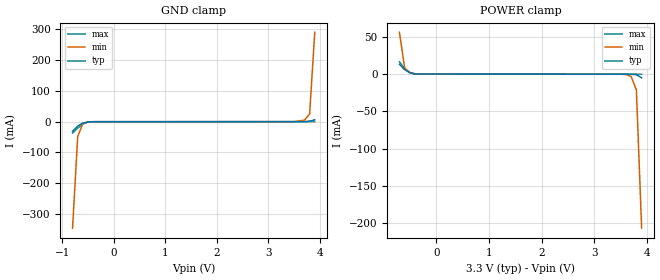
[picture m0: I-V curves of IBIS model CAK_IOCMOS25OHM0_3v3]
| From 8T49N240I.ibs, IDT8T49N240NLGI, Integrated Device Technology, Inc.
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| 3.25758e+00   -2.17526e-02   -5.28437e-01   -1.11612e-02
| 3.33333e+00   -5.02557e-02   -7.41905e-01   -2.20995e-02
| 3.40909e+00   -2.62296e-01   -9.55738e-01   -3.45860e-02
| 3.48485e+00   -5.48283e-01   -1.16984e+00   -4.61839e-02
| 3.56061e+00   -8.34620e-01   -1.38416e+00   -9.03549e-02
| 3.63636e+00   -1.12128e+00   -1.59867e+00   -4.17005e-01
| 3.71212e+00   -1.40822e+00   -1.81336e+00   -7.83863e-01
| 3.78788e+00   -1.69544e+00   -2.02823e+00   -1.15106e+00
| 3.86364e+00   -1.98290e+00   -2.24326e+00   -1.51854e+00
| 3.93939e+00   -2.27059e+00   -2.45845e+00   -1.88629e+00
| 4.01515e+00   -2.55849e+00   -2.67380e+00   -2.25425e+00
| 4.09091e+00   -2.84658e+00   -2.88929e+00   -2.62240e+00
| 4.16667e+00   -3.13483e+00   -3.10491e+00   -2.99072e+00
| 4.24242e+00   -3.42324e+00   -3.32067e+00   -3.35917e+00
| 4.31818e+00   -3.71177e+00   -3.53656e+00   -3.72774e+00
| 4.39394e+00   -4.00043e+00   -3.75256e+00   -4.09641e+00
| 4.46970e+00   -4.28920e+00   -3.96868e+00   -4.46517e+00
| 4.54545e+00   -4.57807e+00   -4.18490e+00   -4.83401e+00
| 4.62121e+00   -4.86701e+00   -4.40122e+00   -5.20293e+00
| 4.69697e+00   -5.15604e+00   -4.61763e+00   -5.57191e+00
| 4.77273e+00   -5.44513e+00   -4.83413e+00   -5.94093e+00
| 4.84848e+00   -5.73428e+00   -5.05072e+00   -6.31000e+00
| 4.92424e+00   -6.02348e+00   -5.26738e+00   -6.67909e+00
| 5.00000e+00   -6.31272e+00   -5.48412e+00   -7.04821e+00
[Model] CAK_IOCMOS25OHM0_3v3
Model_type   Input
Polarity   Non-Inverting
Vinl = 0.8V
Vinh = 2.0V
|   typ   min   max
C_comp   2pF   1.5pF   2.5pF
|   typ   min   max
[Voltage range]   3.3V   3.135V   3.465V
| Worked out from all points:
|   GND clamp passes 1 mA (typ) near -0.50 V on its own axis
|   POWER clamp passes 1 mA (typ) near -0.45 V on its own axis
[GND_clamp]
|Voltage   I (typ)   I (min)   I (max)
|Note, modeling breaks down at 250mA and above.  This is well beyond the functional   |
|operating range of the device.  Should this scenario occur, catastrophic failure and   |
|possible damage to the device and/or board is of higher concern than the I-V curve   |
|behavior.  The IBIS checker will flag currents in excess of 10A with warnings.  Lines   |
|with currents in excess of 0.35 A have been commented out.  The points still remain|
|available to the user if the user desires to use them.   |
|-3.30000e+00   -2.67880e+01   -2.11304e+01   -3.31620e+01
|-3.20000e+00   -2.56708e+01   -2.02932e+01   -3.17348e+01
|-3.10000e+00   -2.45536e+01   -1.94561e+01   -3.03075e+01
|-3.00000e+00   -2.34365e+01   -1.86191e+01   -2.88803e+01
|-2.90000e+00   -2.23193e+01   -1.77821e+01   -2.74530e+01
|-2.80000e+00   -2.12022e+01   -1.69453e+01   -2.60257e+01
|-2.70000e+00   -2.00852e+01   -1.61085e+01   -2.45984e+01
|-2.60000e+00   -1.89682e+01   -1.52719e+01   -2.31711e+01
|-2.50000e+00   -1.78512e+01   -1.44354e+01   -2.17438e+01
|-2.40000e+00   -1.67343e+01   -1.35990e+01   -2.03165e+01
|-2.30000e+00   -1.56175e+01   -1.27628e+01   -1.88893e+01
|-2.20000e+00   -1.45008e+01   -1.19267e+01   -1.74621e+01
|-2.10000e+00   -1.33842e+01   -1.10908e+01   -1.60349e+01
|-2.00000e+00   -1.22678e+01   -1.02551e+01   -1.46078e+01
|-1.90000e+00   -1.11515e+01   -9.41957e+00   -1.31808e+01
|-1.80000e+00   -1.00354e+01   -8.58426e+00   -1.17540e+01
|-1.70000e+00   -8.91950e+00   -7.74918e+00   -1.03273e+01
|-1.60000e+00   -7.80386e+00   -6.91434e+00   -8.90076e+00
|-1.50000e+00   -6.68850e+00   -6.07976e+00   -7.47445e+00
|-1.40000e+00   -5.57349e+00   -5.24546e+00   -6.04840e+00
|-1.30000e+00   -4.45885e+00   -4.41145e+00   -4.62267e+00
|-1.20000e+00   -3.34464e+00   -3.57774e+00   -3.19734e+00
|-1.10000e+00   -2.23090e+00   -2.74437e+00   -1.77249e+00
|-1.00000e+00   -1.11769e+00   -1.91140e+00   -4.23919e-01
|-9.00000e-01   -2.42978e-01   -1.07895e+00   -5.71820e-02
-800mV    -31.58mA   -346.5mA   -37.13mA
-700mV    -14.02mA   -47.95mA   -20.86mA
-600mV    -4.891mA   -5.99mA    -7.57mA
-500mV    -845.1uA   -939.6uA   -1.201mA
-400mV    -124.1uA   -152.8uA   -141.9uA
3.5V      4.074uA    131uA      805.5nA
3.7V      188uA      4.818mA    5.575uA
3.8V      1.749mA    25.01mA    23.47uA
3.9V      6.005mA    290.6mA    518.2uA
| 4.00000e+00   1.31613e-02   1.29161e+00   3.67695e-03
| 4.10000e+00   2.82381e-02   2.43119e+00   1.03297e-02
| 4.20000e+00   3.33592e-01   3.57106e+00   2.01811e-02
| 4.30000e+00   1.73507e+00   4.71130e+00   2.97871e-02
| 4.40000e+00   3.25730e+00   5.85191e+00   7.66204e-02
| 4.50000e+00   4.78003e+00   6.99289e+00   1.34066e+00
| 4.60000e+00   6.30325e+00   8.13425e+00   3.28748e+00
| 4.70000e+00   7.82696e+00   9.27597e+00   5.23493e+00
| 4.80000e+00   9.35115e+00   1.04181e+01   7.18299e+00
| 4.90000e+00   1.08758e+01   1.15605e+01   9.13163e+00
| 5.00000e+00   1.24009e+01   1.27033e+01   1.10808e+01
| 5.10000e+00   1.39264e+01   1.38465e+01   1.30306e+01
| 5.20000e+00   1.54524e+01   1.49901e+01   1.49808e+01
| 5.30000e+00   1.69788e+01   1.61340e+01   1.69316e+01
| 5.40000e+00   1.85056e+01   1.72783e+01   1.88828e+01
| 5.50000e+00   2.00329e+01   1.84230e+01   2.08345e+01
| 5.60000e+00   2.15605e+01   1.95681e+01   2.27867e+01
| 5.70000e+00   2.30886e+01   2.07137e+01   2.47393e+01
| 5.80000e+00   2.46171e+01   2.18596e+01   2.66923e+01
| 5.90000e+00   2.61460e+01   2.30059e+01   2.86458e+01
| 6.00000e+00   2.76753e+01   2.41528e+01   3.05996e+01
| 6.10000e+00   2.92051e+01   2.53000e+01   3.25539e+01
| 6.20000e+00   3.07353e+01   2.64478e+01   3.45086e+01
| 6.30000e+00   3.22660e+01   2.75961e+01   3.64638e+01
| 6.40000e+00   3.37972e+01   2.87449e+01   3.84193e+01
| 6.50000e+00   3.53288e+01   2.98943e+01   4.03753e+01
| 6.60000e+00   3.68610e+01   3.10443e+01   4.23318e+01
[Power_clamp]
|Voltage   I (typ)   I (min)   I (max)
|Note, modeling breaks down at 250mA and above.  This is well beyond the functional   |
|operating range of the device.  Should this scenario occur, catastrophic failure and   |
|possible damage to the device and/or board is of higher concern than the I-V curve   |
|behavior.  The IBIS checker will flag currents in excess of 10A with warnings.  Lines   |
|with currents in excess of 0.35 A have been commented out.  The points still remain|
|available to the user if the user desires to use them.   |
|-3.30000e+00   3.68610e+01   2.91586e+01   4.55611e+01
|-3.20000e+00   3.53288e+01   2.80096e+01   4.36038e+01
|-3.10000e+00   3.37972e+01   2.68611e+01   4.16470e+01
|-3.00000e+00   3.22660e+01   2.57132e+01   3.96907e+01
|-2.90000e+00   3.07353e+01   2.45657e+01   3.77348e+01
|-2.80000e+00   2.92051e+01   2.34187e+01   3.57794e+01
|-2.70000e+00   2.76753e+01   2.22722e+01   3.38244e+01
|-2.60000e+00   2.61460e+01   2.11261e+01   3.18699e+01
|-2.50000e+00   2.46171e+01   1.99805e+01   2.99157e+01
|-2.40000e+00   2.30886e+01   1.88352e+01   2.79620e+01
|-2.30000e+00   2.15605e+01   1.76904e+01   2.60087e+01
|-2.20000e+00   2.00329e+01   1.65459e+01   2.40558e+01
|-2.10000e+00   1.85056e+01   1.54019e+01   2.21034e+01
|-2.00000e+00   1.69788e+01   1.42582e+01   2.01514e+01
|-1.90000e+00   1.54524e+01   1.31148e+01   1.81999e+01
|-1.80000e+00   1.39264e+01   1.19719e+01   1.62488e+01
|-1.70000e+00   1.24009e+01   1.08293e+01   1.42982e+01
|-1.60000e+00   1.08758e+01   9.68708e+00   1.23481e+01
|-1.50000e+00   9.35115e+00   8.54522e+00   1.03986e+01
|-1.40000e+00   7.82696e+00   7.40374e+00   8.44954e+00
|-1.30000e+00   6.30325e+00   6.26262e+00   6.50110e+00
|-1.20000e+00   4.78003e+00   5.12188e+00   4.55325e+00
|-1.10000e+00   3.25730e+00   3.98151e+00   2.60602e+00
|-1.00000e+00   1.73507e+00   2.84150e+00   6.65694e-01
|-9.00000e-01   3.33592e-01   1.70183e+00   4.16232e-02
|-8.00000e-01   2.82381e-02   5.79165e-01   2.67180e-02
-700mV    13.16mA    56.15mA    16.45mA
-600mV    6.005mA    8.033mA    7.61mA
-500mV    1.749mA    1.985mA    2.168mA
-400mV    188uA      310.8uA    178.2uA
3.5V      -69.76uA   -98.2uA    -80.55uA
3.6V      -73.38uA   -468.2uA   -82.85uA
3.7V      -124.1uA   -3.105mA   -85.19uA
3.8V      -845.1uA   -21.26mA   -91.47uA
3.9V      -4.891mA   -207mA     -262.6uA
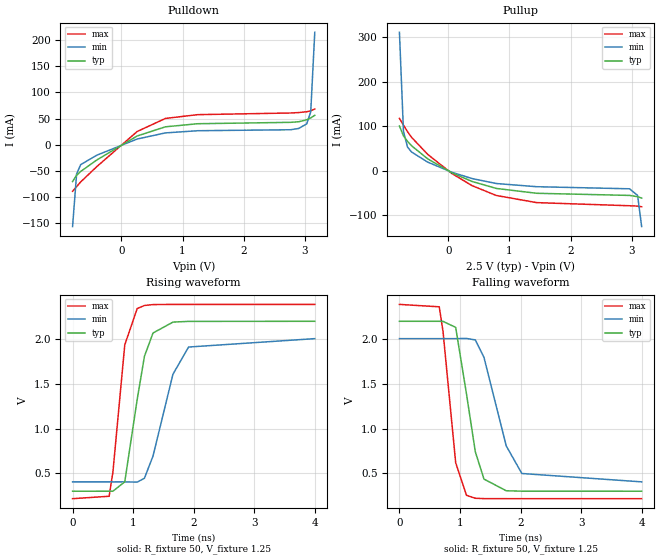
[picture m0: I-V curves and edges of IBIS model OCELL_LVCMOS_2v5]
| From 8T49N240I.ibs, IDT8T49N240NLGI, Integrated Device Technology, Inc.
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[Model] OCELL_LVCMOS_2v5
Model_type   Output
Polarity   Non-Inverting
|   typ   min   max
C_comp   2pF   1.5pF   2.5pF
Vmeas = 1.25V
Rref = 50
Cref = 0
Vref = 1.25V
|   typ   min   max
[Voltage range]   2.5V   2.375V   2.625V
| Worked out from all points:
|   slope of the pulldown table from 0 to 0.375 V, typ, clamps not added: 16.6 ohm
|   slope of the pullup table from 0 to 0.375 V, typ, clamps not added: 16.3 ohm
|   rising waveform, R_fixture 50, V_fixture 1.25: 20-80 % time 250ps typ, 356ps min, 180ps max; typ from 0.3 V to 2.2 V
|   falling waveform, R_fixture 50, V_fixture 1.25: 20-80 % time 254ps typ, 365ps min, 183ps max; typ from 2.2 V to 0.3 V
[Pulldown]
|Voltage   I (typ)   I (min)   I (max)
|Note, modeling breaks down at 250mA and above.  This is well beyond the functional   |
|operating range of the device.  Should this scenario occur, catastrophic failure and   |
|possible damage to the device and/or board is of higher concern than the I-V curve   |
|behavior.  The IBIS checker will flag currents in excess of 10A with warnings.  Lines   |
|with currents in excess of 0.35 A have been commented out.  The points still remain|
|available to the user if the user desires to use them.   |
|-2.20000e+00   -1.47234e+01   -1.29922e+01   -1.76718e+01
|-1.90000e+00   -1.13870e+01   -1.02147e+01   -1.34078e+01
|-1.60000e+00   -8.05069e+00   -7.43744e+00   -9.14425e+00
|-1.30000e+00   -4.71452e+00   -4.66038e+00   -4.88193e+00
|-1.00000e+00   -1.37872e+00   -1.88338e+00   -6.18804e-01
|-9.99000e-01   -1.36761e+00   -1.87412e+00   -6.04590e-01
|-9.32920e-01   -6.32942e-01   -1.26251e+00   -1.30309e-01
|-8.66839e-01   -1.33973e-01   -6.50974e-01   -9.78635e-02
-800.8mV  -70.24mA   -156.4mA   -88.93mA
-734.7mV  -58.48mA   -55.98mA   -80.19mA
-668.6mV  -51.18mA   -38.1mA    -71.19mA
-404.3mV  -29.17mA   -20.02mA   -41.85mA
256.5mV   16.72mA    10.9mA     25.23mA
719.1mV   34.24mA    22.61mA    50.25mA
1.248V    40.16mA    26.79mA    57.49mA
2.768V    42.8mA     28.65mA    60.67mA
2.9V      43.9mA     31.11mA    61.49mA
3.032V    47.65mA    39.85mA    63.04mA
3.098V    51.28mA    62.74mA    64.91mA
3.164V    56.14mA    214.9mA    68.27mA
| 3.23015e+00   6.27700e-02   1.07011e+00   7.31405e-02
| 3.29623e+00   7.75504e-02   2.32136e+00   7.94722e-02
| 3.36231e+00   1.89154e-01   3.57597e+00   8.71327e-02
| 3.42839e+00   1.12551e+00   4.83077e+00   9.48018e-02
| 3.49447e+00   2.63066e+00   6.08576e+00   1.03558e-01
| 3.56055e+00   4.13822e+00   7.34094e+00   1.69861e-01
| 3.62663e+00   5.64602e+00   8.59632e+00   1.20869e+00
| 3.69271e+00   7.15406e+00   9.85190e+00   3.13574e+00
| 3.75879e+00   8.66234e+00   1.11077e+01   5.06397e+00
| 3.82487e+00   1.01709e+01   1.23636e+01   6.99250e+00
| 3.89095e+00   1.16796e+01   1.36198e+01   8.92133e+00
| 3.95703e+00   1.31886e+01   1.48761e+01   1.08505e+01
| 4.02311e+00   1.46979e+01   1.61327e+01   1.27799e+01
| 4.08920e+00   1.62074e+01   1.73894e+01   1.47096e+01
| 4.15528e+00   1.77171e+01   1.86464e+01   1.66397e+01
| 4.22136e+00   1.92271e+01   1.99035e+01   1.85700e+01
| 4.28744e+00   2.07373e+01   2.11609e+01   2.05005e+01
| 4.35352e+00   2.22478e+01   2.24185e+01   2.24314e+01
| 4.41960e+00   2.37585e+01   2.36762e+01   2.43626e+01
| 4.48568e+00   2.52695e+01   2.49342e+01   2.62941e+01
| 4.55176e+00   2.67807e+01   2.61924e+01   2.82260e+01
| 4.61784e+00   2.82921e+01   2.74508e+01   3.01581e+01
| 4.68392e+00   2.98039e+01   2.87095e+01   3.20906e+01
| 4.75000e+00   3.13158e+01   2.99683e+01   3.40234e+01
| 4.75100e+00   3.13387e+01   2.99874e+01   3.40527e+01
| 4.80080e+00   3.24784e+01   3.09363e+01   3.55095e+01
| 4.85060e+00   3.36182e+01   3.18853e+01   3.69666e+01
| 4.90040e+00   3.47581e+01   3.28344e+01   3.84238e+01
| 4.95020e+00   3.58983e+01   3.37837e+01   3.98812e+01
| 5.00000e+00   3.70385e+01   3.47331e+01   4.13388e+01
[Pullup]
|Voltage   I (typ)   I (min)   I (max)
|Note, modeling breaks down at 250mA and above.  This is well beyond the functional   |
|operating range of the device.  Should this scenario occur, catastrophic failure and   |
|possible damage to the device and/or board is of higher concern than the I-V curve   |
|behavior.  The IBIS checker will flag currents in excess of 10A with warnings.  Lines   |
|with currents in excess of 0.35 A have been commented out.  The points still remain|
|available to the user if the user desires to use them.   |
|-2.20000e+00   3.02541e+01   2.67088e+01   3.63095e+01
|-1.90000e+00   2.33839e+01   2.09894e+01   2.75277e+01
|-1.60000e+00   1.65168e+01   1.52730e+01   1.87492e+01
|-1.30000e+00   9.65279e+00   9.55943e+00   9.97348e+00
|-1.00000e+00   2.79120e+00   3.84826e+00   1.20217e+00
|-9.99000e-01   2.76833e+00   3.82923e+00   1.17395e+00
|-9.32920e-01   1.25722e+00   2.57145e+00   1.97091e-01
|-8.66839e-01   2.37533e-01   1.31358e+00   1.32771e-01
-800.8mV  101.1mA    311.5mA    118.1mA
-734.7mV  78.81mA    89.07mA    102.8mA
-668.6mV  66.56mA    53.57mA    88.29mA
-602.5mV  56.6mA     42.56mA    75.59mA
-338.2mV  27.17mA    19.82mA    37.17mA
58.29mV   -4.132mA   -2.995mA   -5.792mA
388.7mV   -23.68mA   -17.13mA   -33.14mA
785.2mV   -39.34mA   -28.29mA   -55.16mA
1.446V    -50.22mA   -35.44mA   -71.2mA
2.966V    -55mA      -40.13mA   -78.22mA
3.098V    -57.9mA    -55.08mA   -78.97mA
3.164V    -61.03mA   -125mA     -80.49mA
| 3.23015e+00   -6.54678e-02   -5.43615e-01   -8.36409e-02
| 3.29623e+00   -7.42145e-02   -1.15365e+00   -8.83529e-02
| 3.36231e+00   -1.27209e-01   -1.76391e+00   -9.42530e-02
| 3.42839e+00   -5.84197e-01   -2.37432e+00   -1.00556e-01
| 3.49447e+00   -1.31730e+00   -2.98487e+00   -1.07568e-01
| 3.56055e+00   -2.05063e+00   -3.59552e+00   -1.41420e-01
| 3.62663e+00   -2.78416e+00   -4.20628e+00   -6.47768e-01
| 3.69271e+00   -3.51789e+00   -4.81712e+00   -1.58557e+00
| 3.75879e+00   -4.25179e+00   -5.42804e+00   -2.52351e+00
| 3.82487e+00   -4.98583e+00   -6.03904e+00   -3.46154e+00
| 3.89095e+00   -5.71999e+00   -6.65012e+00   -4.39967e+00
| 3.95703e+00   -6.45426e+00   -7.26126e+00   -5.33788e+00
| 4.02311e+00   -7.18862e+00   -7.87248e+00   -6.27622e+00
| 4.08920e+00   -7.92307e+00   -8.48376e+00   -7.21475e+00
| 4.15528e+00   -8.65759e+00   -9.09510e+00   -8.15347e+00
| 4.22136e+00   -9.39219e+00   -9.70650e+00   -9.09237e+00
| 4.28744e+00   -1.01269e+01   -1.03180e+01   -1.00314e+01
| 4.35352e+00   -1.08616e+01   -1.09295e+01   -1.09706e+01
| 4.41960e+00   -1.15964e+01   -1.15410e+01   -1.19098e+01
| 4.48568e+00   -1.23312e+01   -1.21527e+01   -1.28491e+01
| 4.55176e+00   -1.30661e+01   -1.27643e+01   -1.37885e+01
| 4.61784e+00   -1.38011e+01   -1.33761e+01   -1.47280e+01
| 4.68392e+00   -1.45361e+01   -1.39878e+01   -1.56675e+01
| 4.75000e+00   -1.52711e+01   -1.45997e+01   -1.66071e+01
| 4.75100e+00   -1.52823e+01   -1.46089e+01   -1.66213e+01
| 4.80080e+00   -1.58363e+01   -1.50701e+01   -1.73295e+01
| 4.85060e+00   -1.63903e+01   -1.55312e+01   -1.80376e+01
| 4.90040e+00   -1.69444e+01   -1.59924e+01   -1.87459e+01
| 4.95020e+00   -1.74985e+01   -1.64536e+01   -1.94541e+01
| 5.00000e+00   -1.80526e+01   -1.69149e+01   -2.01625e+01
[Ramp]
|   typ   min   max
dV/dt_r   1.141/0.25n   0.963/0.356n   1.305/0.18n
dV/dt_f   1.144/0.255n   0.964/0.366n   1.309/0.183n
R_load =   50.0000
[Rising Waveform]
R_fixture = 50
V_fixture = 1.25   |Vcc_typ
V_fixture_min = 1.1875 |Vcc_min
V_fixture_max = 1.3125 |Vcc_max
C_fixture = 0.0p
| Time   typ   min   max
0s        300mV      404.6mV    216.5mV
604.4ps   300.1mV    404.6mV    243.5mV
666.7ps   300.2mV    404.5mV    515.8mV
862.2ps   405.2mV    404.7mV    1.937V
1.067ns   1.325V     401.7mV    2.343V
1.187ns   1.809V     445.1mV    2.378V
1.329ns   2.07V      693.7mV    2.388V
1.658ns   2.192V     1.609V     2.39V
1.916ns   2.2V       1.913V     2.39V
4ns       2.201V     2.007V     2.39V
[Falling Waveform]
R_fixture = 50
V_fixture = 1.25   |Vcc_typ
V_fixture_min = 1.1875 |Vcc_min
V_fixture_max = 1.3125 |Vcc_max
C_fixture = 0.0p
| Time   typ   min   max
0s        2.201V     2.007V     2.39V
657.8ps   2.201V     2.007V     2.363V
720ps     2.2V       2.007V     2.086V
928.9ps   2.133V     2.007V     619.1mV
1.107ns   1.39V      2.009V     254.2mV
1.253ns   741.6mV    1.993V     221.1mV
1.396ns   435.8mV    1.798V     217.1mV
1.764ns   304.7mV    806.2mV    216.5mV
2.022ns   300.5mV    498.1mV    216.5mV
4ns       300mV      404.6mV    216.5mV
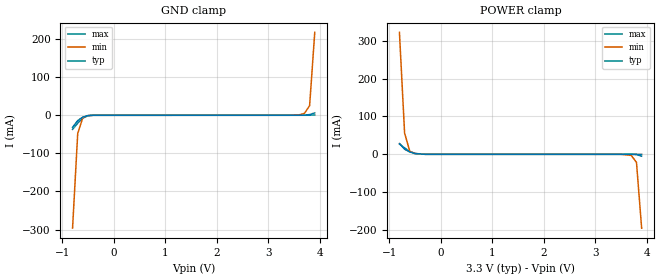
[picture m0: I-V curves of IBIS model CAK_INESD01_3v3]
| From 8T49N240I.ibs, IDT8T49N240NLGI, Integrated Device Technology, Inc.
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| 4.00000e+00   -1.41222e-02   -5.23662e-01   -2.57124e-03
| 4.10000e+00   -3.54868e-02   -8.05387e-01   -1.15576e-02
| 4.20000e+00   -2.75471e-01   -1.08774e+00   -2.65900e-02
| 4.30000e+00   -6.52996e-01   -1.37052e+00   -4.24717e-02
| 4.40000e+00   -1.03112e+00   -1.65365e+00   -1.10054e-01
| 4.50000e+00   -1.40978e+00   -1.93709e+00   -5.78915e-01
| 4.60000e+00   -1.78891e+00   -2.22083e+00   -1.06338e+00
| 4.70000e+00   -2.16847e+00   -2.50485e+00   -1.54839e+00
| 4.80000e+00   -2.54841e+00   -2.78914e+00   -2.03385e+00
| 4.90000e+00   -2.92868e+00   -3.07367e+00   -2.51968e+00
| 5.00000e+00   -3.30923e+00   -3.35844e+00   -3.00580e+00
| 5.10000e+00   -3.69004e+00   -3.64343e+00   -3.49217e+00
| 5.20000e+00   -4.07106e+00   -3.92862e+00   -3.97874e+00
| 5.30000e+00   -4.45227e+00   -4.21400e+00   -4.46548e+00
| 5.40000e+00   -4.83364e+00   -4.49956e+00   -4.95237e+00
| 5.50000e+00   -5.21514e+00   -4.78527e+00   -5.43938e+00
| 5.60000e+00   -5.59676e+00   -5.07114e+00   -5.92648e+00
| 5.70000e+00   -5.97847e+00   -5.35714e+00   -6.41365e+00
| 5.80000e+00   -6.36027e+00   -5.64326e+00   -6.90087e+00
| 5.90000e+00   -6.74214e+00   -5.92951e+00   -7.38812e+00
| 6.00000e+00   -7.12406e+00   -6.21586e+00   -7.87539e+00
| 6.10000e+00   -7.50603e+00   -6.50231e+00   -8.36267e+00
| 6.20000e+00   -7.88804e+00   -6.78886e+00   -8.84995e+00
| 6.30000e+00   -8.27008e+00   -7.07549e+00   -9.33722e+00
| 6.40000e+00   -8.65215e+00   -7.36221e+00   -9.82449e+00
| 6.50000e+00   -9.03423e+00   -7.64900e+00   -1.03117e+01
| 6.60000e+00   -9.41633e+00   -7.93586e+00   -1.07990e+01
[Model] CAK_INESD01_3v3
Model_type   Input
Polarity   Non-Inverting
Vinl = 0.8V
Vinh = 2.0V
|   typ   min   max
C_comp   2pF   1.5pF   2.5pF
|   typ   min   max
[Voltage range]   3.3V   3.135V   3.465V
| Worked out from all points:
|   GND clamp passes 1 mA (typ) near -0.51 V on its own axis
|   POWER clamp passes 1 mA (typ) near -0.45 V on its own axis
[GND_clamp]
|Voltage   I (typ)   I (min)   I (max)
|Note, modeling breaks down at 250mA and above.  This is well beyond the functional   |
|operating range of the device.  Should this scenario occur, catastrophic failure and   |
|possible damage to the device and/or board is of higher concern than the I-V curve   |
|behavior.  The IBIS checker will flag currents in excess of 10A with warnings.  Lines   |
|with currents in excess of 0.35 A have been commented out.  The points still remain|
|available to the user if the user desires to use them.   |
|-3.30000e+00   -9.36876e+00   -7.41789e+00   -1.15553e+01
|-3.20000e+00   -8.98667e+00   -7.13115e+00   -1.10681e+01
|-3.10000e+00   -8.60459e+00   -6.84449e+00   -1.05809e+01
|-3.00000e+00   -8.22253e+00   -6.55791e+00   -1.00936e+01
|-2.90000e+00   -7.84049e+00   -6.27142e+00   -9.60637e+00
|-2.80000e+00   -7.45848e+00   -5.98504e+00   -9.11911e+00
|-2.70000e+00   -7.07651e+00   -5.69875e+00   -8.63183e+00
|-2.60000e+00   -6.69459e+00   -5.41259e+00   -8.14455e+00
|-2.50000e+00   -6.31272e+00   -5.12654e+00   -7.65728e+00
|-2.40000e+00   -5.93093e+00   -4.84063e+00   -7.17002e+00
|-2.30000e+00   -5.54921e+00   -4.55486e+00   -6.68278e+00
|-2.20000e+00   -5.16760e+00   -4.26925e+00   -6.19558e+00
|-2.10000e+00   -4.78610e+00   -3.98381e+00   -5.70844e+00
|-2.00000e+00   -4.40474e+00   -3.69855e+00   -5.22138e+00
|-1.90000e+00   -4.02353e+00   -3.41349e+00   -4.73442e+00
|-1.80000e+00   -3.64251e+00   -3.12864e+00   -4.24759e+00
|-1.70000e+00   -3.26171e+00   -2.84402e+00   -3.76091e+00
|-1.60000e+00   -2.88116e+00   -2.55965e+00   -3.27441e+00
|-1.50000e+00   -2.50090e+00   -2.27553e+00   -2.78813e+00
|-1.40000e+00   -2.12097e+00   -1.99169e+00   -2.30210e+00
|-1.30000e+00   -1.74142e+00   -1.70814e+00   -1.81640e+00
|-1.20000e+00   -1.36229e+00   -1.42490e+00   -1.33109e+00
|-1.10000e+00   -9.83643e-01   -1.14199e+00   -8.46264e-01
|-1.00000e+00   -6.05524e-01   -8.59476e-01   -3.62007e-01
|-9.00000e-01   -2.28002e-01   -5.77494e-01   -5.70861e-02
-800mV    -31.5mA    -296.3mA   -37.03mA
-700mV    -13.94mA   -47.89mA   -20.77mA
-600mV    -4.814mA   -5.925mA   -7.477mA
-500mV    -769.5uA   -876.2uA   -1.11mA
-400mV    -50.39uA   -91.12uA   -52.98uA
3.4V      929.4pA    7.738uA    18.23pA
3.6V      7.536uA    1.177mA    576.1pA
3.7V      200.6uA    4.949mA    206.1nA
3.8V      1.845mA    25.21mA    18.18uA
3.9V      6.193mA    217.6mA    563.4uA
| 4.00000e+00   1.34293e-02   5.06540e-01   3.84286e-03
| 4.10000e+00   2.85679e-02   7.94900e-01   1.06020e-02
| 4.20000e+00   2.42102e-01   1.08355e+00   2.05441e-02
| 4.30000e+00   6.27135e-01   1.37257e+00   3.02103e-02
| 4.40000e+00   1.01263e+00   1.66196e+00   7.70913e-02
| 4.50000e+00   1.39863e+00   1.95172e+00   5.37431e-01
| 4.60000e+00   1.78513e+00   2.24185e+00   1.03062e+00
| 4.70000e+00   2.17212e+00   2.53235e+00   1.52443e+00
| 4.80000e+00   2.55958e+00   2.82322e+00   2.01885e+00
| 4.90000e+00   2.94751e+00   3.11446e+00   2.51386e+00
| 5.00000e+00   3.33588e+00   3.40606e+00   3.00943e+00
| 5.10000e+00   3.72470e+00   3.69803e+00   3.50553e+00
| 5.20000e+00   4.11396e+00   3.99038e+00   4.00216e+00
| 5.30000e+00   4.50363e+00   4.28310e+00   4.49928e+00
| 5.40000e+00   4.89373e+00   4.57620e+00   4.99688e+00
| 5.50000e+00   5.28425e+00   4.86969e+00   5.49495e+00
| 5.60000e+00   5.67518e+00   5.16358e+00   5.99346e+00
| 5.70000e+00   6.06653e+00   5.45787e+00   6.49241e+00
| 5.80000e+00   6.45829e+00   5.75259e+00   6.99179e+00
| 5.90000e+00   6.85048e+00   6.04774e+00   7.49160e+00
| 6.00000e+00   7.24309e+00   6.34335e+00   7.99183e+00
| 6.10000e+00   7.63615e+00   6.63943e+00   8.49248e+00
| 6.20000e+00   8.02966e+00   6.93599e+00   8.99355e+00
| 6.30000e+00   8.42363e+00   7.23307e+00   9.49506e+00
| 6.40000e+00   8.81808e+00   7.53069e+00   9.99700e+00
| 6.50000e+00   9.21303e+00   7.82887e+00   1.04994e+01
| 6.60000e+00   9.60850e+00   8.12763e+00   1.10022e+01
[Power_clamp]
|Voltage   I (typ)   I (min)   I (max)
|Note, modeling breaks down at 250mA and above.  This is well beyond the functional   |
|operating range of the device.  Should this scenario occur, catastrophic failure and   |
|possible damage to the device and/or board is of higher concern than the I-V curve   |
|behavior.  The IBIS checker will flag currents in excess of 10A with warnings.  Lines   |
|with currents in excess of 0.35 A have been commented out.  The points still remain|
|available to the user if the user desires to use them.   |
|-3.30000e+00   9.60850e+00   7.63797e+00   1.18330e+01
|-3.20000e+00   9.21303e+00   7.34015e+00   1.13293e+01
|-3.10000e+00   8.81808e+00   7.04288e+00   1.08262e+01
|-3.00000e+00   8.42363e+00   6.74613e+00   1.03235e+01
|-2.90000e+00   8.02966e+00   6.44988e+00   9.82127e+00
|-2.80000e+00   7.63615e+00   6.15411e+00   9.31948e+00
|-2.70000e+00   7.24309e+00   5.85879e+00   8.81813e+00
|-2.60000e+00   6.85048e+00   5.56392e+00   8.31720e+00
|-2.50000e+00   6.45829e+00   5.26948e+00   7.81670e+00
|-2.40000e+00   6.06653e+00   4.97544e+00   7.31662e+00
|-2.30000e+00   5.67518e+00   4.68181e+00   6.81696e+00
|-2.20000e+00   5.28425e+00   4.38857e+00   6.31773e+00
|-2.10000e+00   4.89373e+00   4.09571e+00   5.81893e+00
|-2.00000e+00   4.50363e+00   3.80323e+00   5.32057e+00
|-1.90000e+00   4.11396e+00   3.51113e+00   4.82267e+00
|-1.80000e+00   3.72470e+00   3.21939e+00   4.32523e+00
|-1.70000e+00   3.33588e+00   2.92802e+00   3.82828e+00
|-1.60000e+00   2.94751e+00   2.63702e+00   3.33184e+00
|-1.50000e+00   2.55958e+00   2.34639e+00   2.83591e+00
|-1.40000e+00   2.17212e+00   2.05612e+00   2.34054e+00
|-1.30000e+00   1.78513e+00   1.76623e+00   1.84573e+00
|-1.20000e+00   1.39863e+00   1.47670e+00   1.35152e+00
|-1.10000e+00   1.01263e+00   1.18756e+00   8.57930e-01
|-1.00000e+00   6.27135e-01   8.98775e-01   3.64964e-01
|-9.00000e-01   2.42102e-01   6.10330e-01   4.20775e-02
-800mV    28.57mA    321.9mA    27.12mA
-700mV    13.43mA    56.36mA    16.78mA
-600mV    6.193mA    8.187mA    7.847mA
-500mV    1.845mA    2.071mA    2.293mA
-300mV    7.536uA    23.16uA    4.595uA
3.5V      -38.15nA   -37.11uA   -1.389nA
3.7V      -50.39uA   -3.041mA   -40.99nA
3.8V      -769.5uA   -21.19mA   -4.022uA
3.9V      -4.814mA   -194.9mA   -172.8uA
